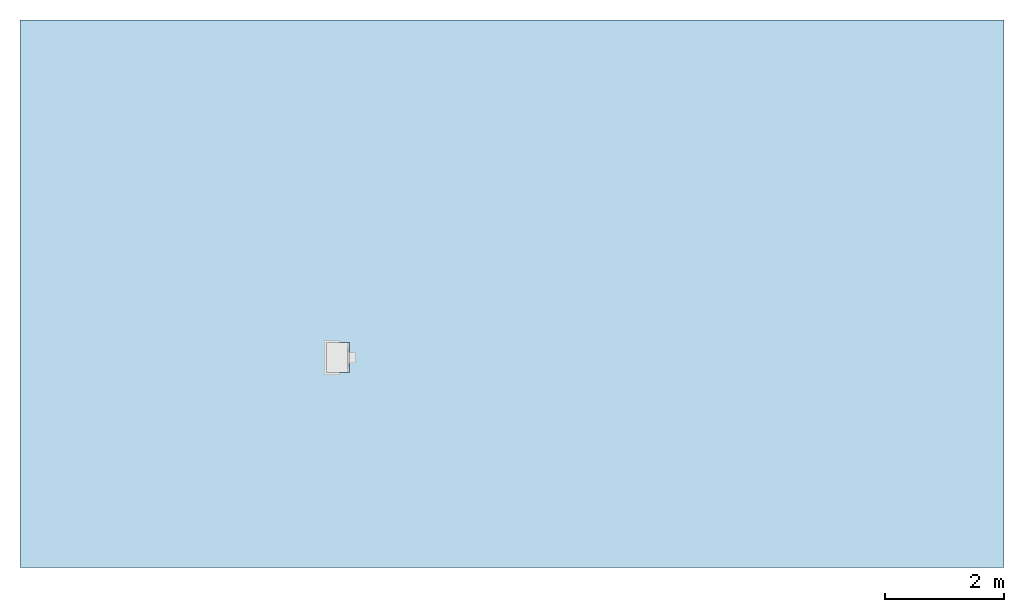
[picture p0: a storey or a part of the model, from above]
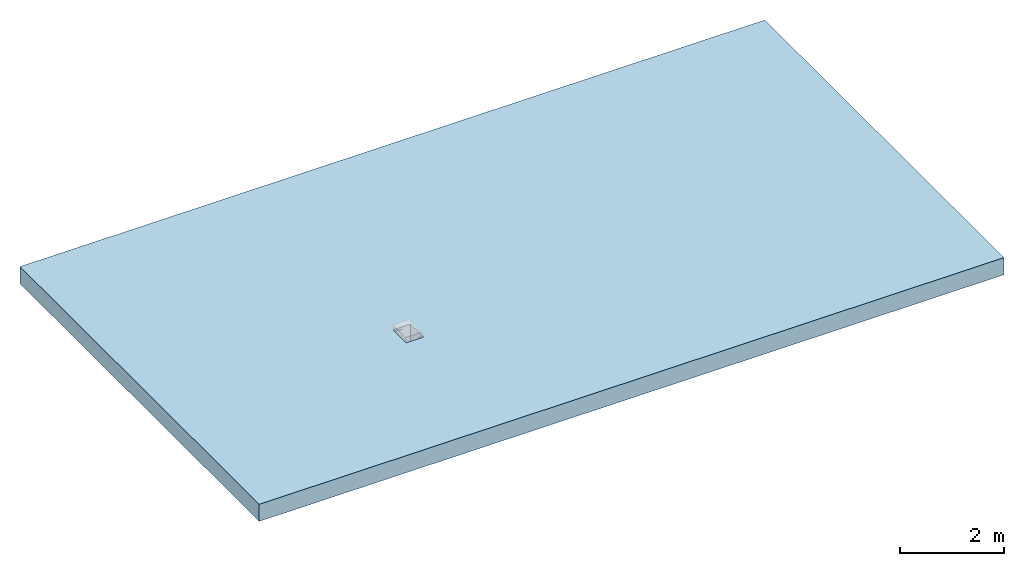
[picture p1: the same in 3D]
Properties of the parts of a building model (IFC2X3)

# File
Description: ViewDefinition [CoordinationView]
File name: 4184 - Top and roddable deep base assembly - KD612RE.ifc
Time: 2013-09-04T09:39:51
Written by: Autodesk Revit 2013
Made in: 20120221_2030(x64)

# IfcProject, Project Number
LongName: Project Name; Phase: Project Status

# IfcSite, Default
RefLatitude: 42, 21, 30, 344238; RefLongitude: -71, -3, -35, -194702; RefElevation: 0 mm

# IfcBuilding
Pset_BuildingCommon - NumberOfStoreys: 1
Other - Client Name: Owner; Project Address: ## Street City, State Zip; Project Status: Project Status; Project Number: Project Number; Project Name: Project Name; Project Issue Date: Issue Date

# IfcBuildingStorey, Level 1
LongName: Level 1; Elevation: 0 mm
Constraints - Elevation Base: 0; Elevation: 0 mm
Graphics - Line Weight: 1; Symbol at End 2 Default: yes; Color: 0; Line Pattern: Center; Symbol: M_Level Head - Circle: M_Level Head - Circle; Symbol at End 1 Default: no
Identity Data - Name: Level 1; Structural: no; Building Story: yes
Dimensions - Computation Height: 0 mm

# IfcBuildingElementProxy: 4184 - Top and roddable deep base assembly - KD612RE, Civil-Drainage-Channel-ACO-KerbDrain-HB Gully units:4184 - Top and roddable deep base assembly - KD612RE:4184 - Top and roddable deep base assembly - KD612RE:309626
In: Level 1
Material: Cast Iron, ACO Polmer Concrete., Gully Colour
Green Building Properties - Gully Base Recycled Material Content: 20% minimum; Gully Base Recyclable: Fully recyclable; Gully Cover/Frame Recycled Material Content: Between 40% - 90%; Gully Cover/Frame Recyclable: Fully recyclable
Phasing - Phase Created: New Construction
Constraints - Moves With Nearby Elements: no; Level: Level: Level 1
Dimensions - Volume: 43804180 mm3; Deep Base Void Depth: 380 mm; Gully Connector Void End: 2005 mm; Shallow Base Depth: 6000 mm; Gully Connector Void Start: 2000 mm; Top and bottom 4979 void depth: 437.065 mm
Pset_BuildingElementProxyCommon - Reference: 4184 - Top and roddable deep base assembly - KD612RE
Identity Data - Cost: 0; Telephone: +44 (0)1462 816666; Assembly Description: Rain Water Drainage; Type Comments: ACO KerbDrain Half Battered Gully Units - Top & Roddable Deep Base Assembly KD612RE; Model: ACO KerbDrain Half Battered Gully Units; Product Code: 4184; URL: www.aco.co.uk; OmniClass Title: Rainwater Removal; Maintenance guidelines: http://www.aco.co.uk/download.php?id=120; Product brochure: http://www.aco.co.uk/download.php?id=120; e-mail Sales: customersupport@aco.co.uk; Manufacturer: ACO Technologies plc - ACO Water Management Division; Price: POA - contact ACO; Address: ACO Business Park, Hitchin Road, Shefford, Bedfordshire, United Kingdom SG17 5TE; Model Description: Combined kerb and drainage system; Assembly Code: D2040; Installation guidelines: http://www.aco.co.uk/download.php?id=120; Product Page URL: http://www.aco.co.uk/product_detail.php?id=3; e-mail Technical: technical@aco.co.uk; OmniClass Number: 23.70.50.24; Fax: +44 (0)1462 815895
Other - Revision: 1; CreatedBy: www.aco.co.uk
General - TagNumber: 0.000000; SerialNumber: 0.000000
Data - Product Dimensions: 500mm x 390mm x 1025mm (LxWxH); Drainage Slot Width: 50mm; Product Standard: BS EN 1433:2002, CE marked, Kitemarked; Invert Depth: 750/780mm; Product Weight: 126.5 Kg; Hydraulic Performance: http://www.aco.co.uk/download.php?id=120; Drainage Slot Intake area: 14592mm²/m; Load Class: A 15 - D 400; Installation - Concrete Grade: Refer to brochure; ACO Hydraulic Design Software: http://www.acodesign.co.uk
Construction - Top and road gully connector: no; Deep Base: yes; Top and roddable deep base assembly KD612RE: yes; Top assembly: yes; Shallow base: no
Materials and Finishes - Gully Cover/Frame Colour: Black; Gully Cover/Frame Material: Ductile Iron; Gully Cover/Frame Finish: Water Based Paint Coating; Gully Base Colour: Brown; Gully Base Material: Vienite® Synthetic Resin Concrete

# IfcOpeningElement: Opening (3)
In: Level 1
Constraints - Level: Level: Level 1; Related to Mass: no; Height Offset From Level: 0 mm; Room Bounding: yes
Dimensions - Volume: 60509758284 mm3; Area: 151309464 mm2; Thickness: 400 mm; Perimeter: 51360 mm
Phasing - Phase Created: New Construction
Structural - Enable Analytical Model: no; Structural: no
Analytical Properties - Absorptance: 0.1; Roughness: 1
Graphics - Coarse Scale Fill Color: 0
Construction - Function: 0; Default Thickness: 400 mm
Materials and Finishes - Structural Material: Plant

# IfcSlab: Floor:Generic Floor - 400mm, Floor:Generic Floor - 400mm:193825
In: Level 1
PredefinedType: FLOOR; Material: Plant 400 mm
Constraints - Level: Level: Level 1; Related to Mass: no; Height Offset From Level: 0 mm; Room Bounding: yes
Dimensions - Volume: 60509758284 mm3; Area: 151309464 mm2; Thickness: 400 mm; Perimeter: 51360 mm
Phasing - Phase Created: New Construction
Structural - Enable Analytical Model: no; Structural: no
Pset_SlabCommon - Reference: Generic Floor - 400mm; IsExternal: no; LoadBearing: yes
Analytical Properties - Absorptance: 0.1; Roughness: 1
Graphics - Coarse Scale Fill Color: 0
Construction - Function: 0; Default Thickness: 400 mm
Materials and Finishes - Structural Material: Plant
